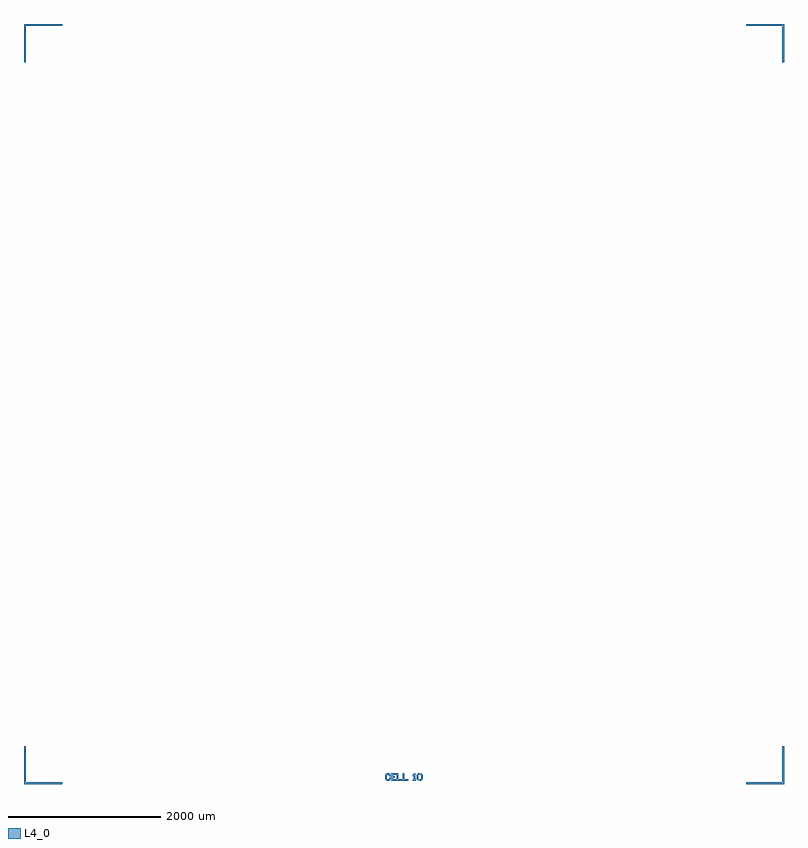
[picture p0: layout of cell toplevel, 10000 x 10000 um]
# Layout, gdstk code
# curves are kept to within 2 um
import gdstk
lib = gdstk.Library(unit=1e-6, precision=1e-09)
def P(c, l, *ps):  # polygons
    for p in ps: c.add(gdstk.Polygon(p, *l))
L4_0 = (4, 0)

toplevel = lib.new_cell('toplevel')
P(toplevel, L4_0, [(5000,5000),(5000,4500),(4980,4500),(4980,4980),(4500,4980),(4500,5000)],
  [(-5000,5000),(-5000,4500),(-4980,4500),(-4980,4980),(-4500,4980),(-4500,5000)],
  [(5000,-5000),(5000,-4500),(4980,-4500),(4980,-4980),(4500,-4980),(4500,-5000)],
  [(-5000,-5000),(-5000,-4500),(-4980,-4500),(-4980,-4980),(-4500,-4980),(-4500,-5000)],
  [(-225,-4960),(-245,-4940),(-245,-4880),(-225,-4860),(-195,-4860),(-175,-4880),(-175,-4900),(-195,-4900),(-195,-4890),(-205,-4880),(-215,-4880),(-225,-4890),(-225,-4930),(-215,-4940),(-205,-4940),(-195,-4930),(-195,-4920),(-175,-4920),(-175,-4940),(-195,-4960)],
  [(-105,-4860),(-105,-4880),(-145,-4880),(-145,-4900),(-125,-4900),(-125,-4920),(-145,-4920),(-145,-4940),(-105,-4940),(-105,-4960),(-165,-4960),(-165,-4860),(-105,-4860)],
  [(-95,-4860),(-75,-4860),(-75,-4940),(-25,-4940),(-25,-4960),(-95,-4960),(-95,-4860)],
  [(-15,-4860),(5,-4860),(5,-4940),(55,-4940),(55,-4960),(-15,-4960),(-15,-4860)],
  [(125,-4900),(115,-4900),(115,-4880),(135,-4860),(145,-4860),(145,-4940),(155,-4940),(155,-4960),(115,-4960),(115,-4940),(125,-4940)],
  [(195,-4880),(185,-4890),(185,-4930),(195,-4940),(190,-4960),(185,-4960),(165,-4940),(165,-4880),(185,-4860),(208,-4860),(203,-4880),(195,-4880)],
  [(215,-4940),(225,-4930),(225,-4890),(215,-4880),(220,-4860),(225,-4860),(245,-4880),(245,-4940),(225,-4960),(202,-4960),(207,-4940),(215,-4940)])

lib.write_gds('toplevel.gds')
